One B-rep face of a CAD part: STEP entity #271.
In plain terms, the planar face has unit normal (1, 0, 0).
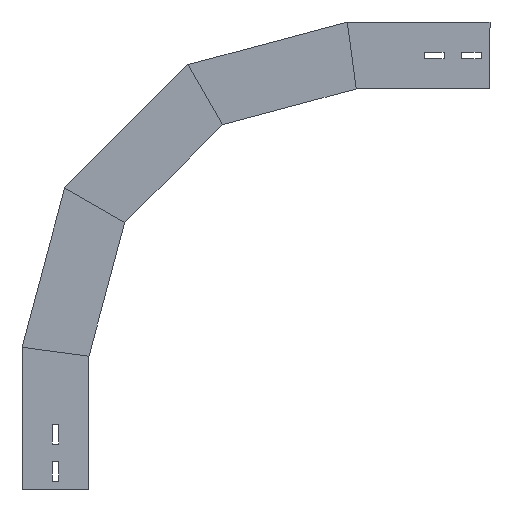
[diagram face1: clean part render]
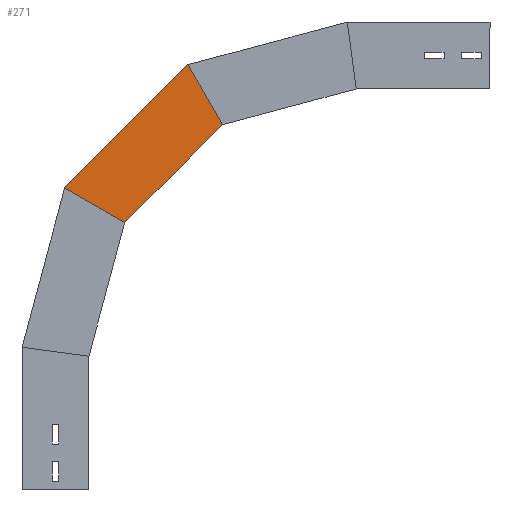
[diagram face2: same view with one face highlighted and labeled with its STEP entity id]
Its self-contained STEP definition (entity closure, numbers rounded to 3 decimals):
#48 = VERTEX_POINT ( 'NONE', #1722 ) ;
#86 = CARTESIAN_POINT ( 'NONE',  ( 0., -77.316, 278.242 ) ) ;
#95 = CARTESIAN_POINT ( 'NONE',  ( 0., -24.415, 284.017 ) ) ;
#114 = DIRECTION ( 'NONE',  ( 0., -0.707, 0.707 ) ) ;
#170 = ORIENTED_EDGE ( 'NONE', *, *, #1172, .F. ) ;
#271 = ADVANCED_FACE ( 'NONE', ( #1358 ), #1647, .T. ) ;
#297 = DIRECTION ( 'NONE',  ( 0., -0.5, -0.866 ) ) ;
#320 = VECTOR ( 'NONE', #114, 1000. ) ;
#389 = DIRECTION ( 'NONE',  ( 0., -0.707, 0.707 ) ) ;
#465 = CARTESIAN_POINT ( 'NONE',  ( 0., -24.415, 284.017 ) ) ;
#480 = VERTEX_POINT ( 'NONE', #1316 ) ;
#526 = EDGE_CURVE ( 'NONE', #48, #1057, #1370, .T. ) ;
#566 = EDGE_CURVE ( 'NONE', #48, #1646, #663, .T. ) ;
#663 = LINE ( 'NONE', #1850, #320 ) ;
#809 = LINE ( 'NONE', #95, #1246 ) ;
#842 = EDGE_CURVE ( 'NONE', #1646, #480, #1319, .T. ) ;
#899 = DIRECTION ( 'NONE',  ( 0., 0., -1. ) ) ;
#927 = CARTESIAN_POINT ( 'NONE',  ( 0., -40.117, 299.719 ) ) ;
#983 = VECTOR ( 'NONE', #1678, 1000. ) ;
#1057 = VERTEX_POINT ( 'NONE', #927 ) ;
#1075 = EDGE_LOOP ( 'NONE', ( #1784, #1357, #170, #1599 ) ) ;
#1172 = EDGE_CURVE ( 'NONE', #1057, #480, #809, .T. ) ;
#1246 = VECTOR ( 'NONE', #389, 1000. ) ;
#1316 = CARTESIAN_POINT ( 'NONE',  ( 0., -149.719, 409.32 ) ) ;
#1319 = LINE ( 'NONE', #1603, #1704 ) ;
#1357 = ORIENTED_EDGE ( 'NONE', *, *, #842, .T. ) ;
#1358 = FACE_OUTER_BOUND ( 'NONE', #1075, .T. ) ;
#1370 = LINE ( 'NONE', #86, #983 ) ;
#1445 = AXIS2_PLACEMENT_3D ( 'NONE', #465, #1803, #899 ) ;
#1599 = ORIENTED_EDGE ( 'NONE', *, *, #526, .F. ) ;
#1603 = CARTESIAN_POINT ( 'NONE',  ( 0., -172.651, 369.6 ) ) ;
#1646 = VERTEX_POINT ( 'NONE', #1686 ) ;
#1647 = PLANE ( 'NONE',  #1445 ) ;
#1678 = DIRECTION ( 'NONE',  ( 0., -0.866, -0.5 ) ) ;
#1686 = CARTESIAN_POINT ( 'NONE',  ( 0., -110.896, 476.563 ) ) ;
#1704 = VECTOR ( 'NONE', #297, 1000. ) ;
#1722 = CARTESIAN_POINT ( 'NONE',  ( 0., 27.126, 338.541 ) ) ;
#1784 = ORIENTED_EDGE ( 'NONE', *, *, #566, .T. ) ;
#1803 = DIRECTION ( 'NONE',  ( 1., 0., 0. ) ) ;
#1850 = CARTESIAN_POINT ( 'NONE',  ( 0., 28.618, 337.05 ) ) ;
